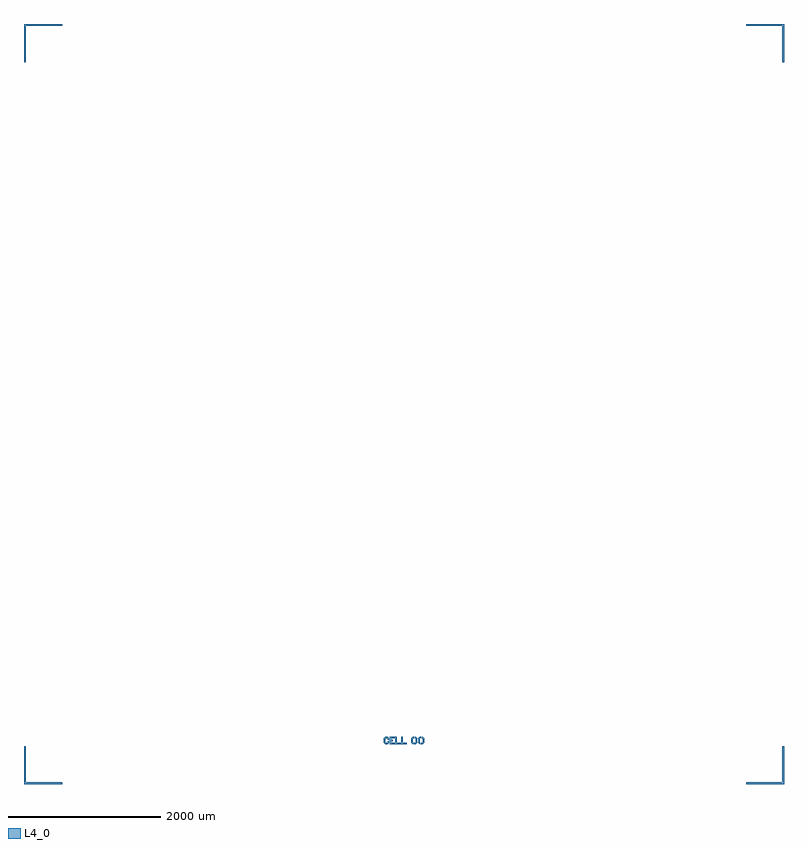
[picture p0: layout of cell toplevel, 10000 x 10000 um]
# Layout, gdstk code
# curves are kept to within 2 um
import gdstk
lib = gdstk.Library(unit=1e-6, precision=1e-09)
def P(c, l, *ps):  # polygons
    for p in ps: c.add(gdstk.Polygon(p, *l))
L4_0 = (4, 0)

toplevel = lib.new_cell('toplevel')
P(toplevel, L4_0, [(5000,5000),(5000,4500),(4980,4500),(4980,4980),(4500,4980),(4500,5000)],
  [(-5000,5000),(-5000,4500),(-4980,4500),(-4980,4980),(-4500,4980),(-4500,5000)],
  [(5000,-5000),(5000,-4500),(4980,-4500),(4980,-4980),(4500,-4980),(4500,-5000)],
  [(-5000,-5000),(-5000,-4500),(-4980,-4500),(-4980,-4980),(-4500,-4980),(-4500,-5000)],
  [(-245,-4480),(-265,-4460),(-265,-4400),(-245,-4380),(-215,-4380),(-195,-4400),(-195,-4420),(-215,-4420),(-215,-4410),(-225,-4400),(-235,-4400),(-245,-4410),(-245,-4450),(-235,-4460),(-225,-4460),(-215,-4450),(-215,-4440),(-195,-4440),(-195,-4460),(-215,-4480)],
  [(-125,-4380),(-125,-4400),(-165,-4400),(-165,-4420),(-145,-4420),(-145,-4440),(-165,-4440),(-165,-4460),(-125,-4460),(-125,-4480),(-185,-4480),(-185,-4380),(-125,-4380)],
  [(-115,-4380),(-95,-4380),(-95,-4460),(-45,-4460),(-45,-4480),(-115,-4480),(-115,-4380)],
  [(-35,-4380),(-15,-4380),(-15,-4460),(35,-4460),(35,-4480),(-35,-4480),(-35,-4380)],
  [(125,-4400),(115,-4410),(115,-4450),(125,-4460),(120,-4480),(115,-4480),(95,-4460),(95,-4400),(115,-4380),(138,-4380),(133,-4400),(125,-4400)],
  [(145,-4460),(155,-4450),(155,-4410),(145,-4400),(150,-4380),(155,-4380),(175,-4400),(175,-4460),(155,-4480),(132,-4480),(137,-4460),(145,-4460)],
  [(215,-4400),(205,-4410),(205,-4450),(215,-4460),(210,-4480),(205,-4480),(185,-4460),(185,-4400),(205,-4380),(228,-4380),(223,-4400),(215,-4400)],
  [(235,-4460),(245,-4450),(245,-4410),(235,-4400),(240,-4380),(245,-4380),(265,-4400),(265,-4460),(245,-4480),(222,-4480),(227,-4460),(235,-4460)])

lib.write_gds('toplevel.gds')
